VERSION 5.7 ;
  NOWIREEXTENSIONATPIN ON ;
  DIVIDERCHAR "/" ;
  BUSBITCHARS "[]" ;
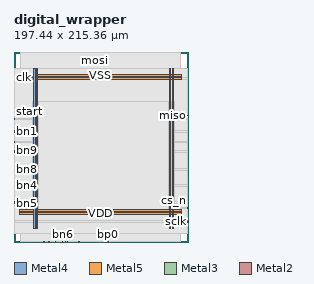
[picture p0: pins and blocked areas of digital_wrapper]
MACRO digital_wrapper
  CLASS BLOCK ;
  FOREIGN digital_wrapper ;
  ORIGIN 0.000 0.000 ;
  SIZE 197.440 BY 215.360 ;
  PIN VDD
    DIRECTION INOUT ;
    USE POWER ;
    PORT
      LAYER Metal4 ;
        RECT 22.240 15.380 23.840 196.300 ;
    END
    PORT
      LAYER Metal4 ;
        RECT 175.840 15.380 177.440 196.300 ;
    END
    PORT
      LAYER Metal5 ;
        RECT 6.720 31.530 190.400 33.130 ;
    END
    PORT
      LAYER Metal5 ;
        RECT 6.720 184.710 190.400 186.310 ;
    END
  END VDD
  PIN VSS
    DIRECTION INOUT ;
    USE GROUND ;
    PORT
      LAYER Metal4 ;
        RECT 25.540 15.380 27.140 196.300 ;
    END
    PORT
      LAYER Metal4 ;
        RECT 179.140 15.380 180.740 196.300 ;
    END
    PORT
      LAYER Metal5 ;
        RECT 6.720 34.830 190.400 36.430 ;
    END
    PORT
      LAYER Metal5 ;
        RECT 6.720 188.010 190.400 189.610 ;
    END
  END VSS
  PIN bist_en
    DIRECTION OUTPUT ;
    USE SIGNAL ;
    ANTENNADIFFAREA 0.360800 ;
    PORT
      LAYER Metal3 ;
        RECT 196.880 22.400 197.440 22.960 ;
    END
  END bist_en
  PIN bn0
    DIRECTION OUTPUT ;
    USE SIGNAL ;
    ANTENNADIFFAREA 0.897600 ;
    PORT
      LAYER Metal2 ;
        RECT 105.280 0.000 105.840 0.560 ;
    END
  END bn0
  PIN bn1
    DIRECTION OUTPUT ;
    USE SIGNAL ;
    ANTENNADIFFAREA 0.897600 ;
    PORT
      LAYER Metal3 ;
        RECT 0.000 125.440 0.560 126.000 ;
    END
  END bn1
  PIN bn2
    DIRECTION OUTPUT ;
    USE SIGNAL ;
    ANTENNADIFFAREA 0.897600 ;
    PORT
      LAYER Metal2 ;
        RECT 47.040 0.000 47.600 0.560 ;
    END
  END bn2
  PIN bn3
    DIRECTION OUTPUT ;
    USE SIGNAL ;
    ANTENNADIFFAREA 0.897600 ;
    PORT
      LAYER Metal2 ;
        RECT 60.480 0.000 61.040 0.560 ;
    END
  END bn3
  PIN bn4
    DIRECTION OUTPUT ;
    USE SIGNAL ;
    ANTENNADIFFAREA 0.897600 ;
    PORT
      LAYER Metal3 ;
        RECT 0.000 63.840 0.560 64.400 ;
    END
  END bn4
  PIN bn5
    DIRECTION OUTPUT ;
    USE SIGNAL ;
    ANTENNADIFFAREA 0.897600 ;
    PORT
      LAYER Metal3 ;
        RECT 0.000 43.680 0.560 44.240 ;
    END
  END bn5
  PIN bn6
    DIRECTION OUTPUT ;
    USE SIGNAL ;
    ANTENNADIFFAREA 0.897600 ;
    PORT
      LAYER Metal2 ;
        RECT 54.880 0.000 55.440 0.560 ;
    END
  END bn6
  PIN bn7
    DIRECTION OUTPUT ;
    USE SIGNAL ;
    ANTENNADIFFAREA 0.897600 ;
    PORT
      LAYER Metal2 ;
        RECT 33.600 0.000 34.160 0.560 ;
    END
  END bn7
  PIN bn8
    DIRECTION OUTPUT ;
    USE SIGNAL ;
    ANTENNADIFFAREA 0.897600 ;
    PORT
      LAYER Metal3 ;
        RECT 0.000 81.760 0.560 82.320 ;
    END
  END bn8
  PIN bn9
    DIRECTION OUTPUT ;
    USE SIGNAL ;
    ANTENNADIFFAREA 0.897600 ;
    PORT
      LAYER Metal3 ;
        RECT 0.000 103.040 0.560 103.600 ;
    END
  END bn9
  PIN bp0
    DIRECTION OUTPUT ;
    USE SIGNAL ;
    ANTENNADIFFAREA 0.897600 ;
    PORT
      LAYER Metal2 ;
        RECT 106.400 0.000 106.960 0.560 ;
    END
  END bp0
  PIN bp1
    DIRECTION OUTPUT ;
    USE SIGNAL ;
    ANTENNADIFFAREA 0.897600 ;
    PORT
      LAYER Metal3 ;
        RECT 0.000 124.320 0.560 124.880 ;
    END
  END bp1
  PIN bp2
    DIRECTION OUTPUT ;
    USE SIGNAL ;
    ANTENNADIFFAREA 0.897600 ;
    PORT
      LAYER Metal2 ;
        RECT 58.240 0.000 58.800 0.560 ;
    END
  END bp2
  PIN bp3
    DIRECTION OUTPUT ;
    USE SIGNAL ;
    ANTENNADIFFAREA 0.897600 ;
    PORT
      LAYER Metal2 ;
        RECT 73.920 0.000 74.480 0.560 ;
    END
  END bp3
  PIN bp4
    DIRECTION OUTPUT ;
    USE SIGNAL ;
    ANTENNADIFFAREA 0.897600 ;
    PORT
      LAYER Metal3 ;
        RECT 0.000 62.720 0.560 63.280 ;
    END
  END bp4
  PIN bp5
    DIRECTION OUTPUT ;
    USE SIGNAL ;
    ANTENNADIFFAREA 0.897600 ;
    PORT
      LAYER Metal3 ;
        RECT 0.000 44.800 0.560 45.360 ;
    END
  END bp5
  PIN bp6
    DIRECTION OUTPUT ;
    USE SIGNAL ;
    ANTENNADIFFAREA 0.897600 ;
    PORT
      LAYER Metal2 ;
        RECT 72.800 0.000 73.360 0.560 ;
    END
  END bp6
  PIN bp7
    DIRECTION OUTPUT ;
    USE SIGNAL ;
    ANTENNADIFFAREA 0.897600 ;
    PORT
      LAYER Metal2 ;
        RECT 39.200 0.000 39.760 0.560 ;
    END
  END bp7
  PIN bp8
    DIRECTION OUTPUT ;
    USE SIGNAL ;
    ANTENNADIFFAREA 0.897600 ;
    PORT
      LAYER Metal3 ;
        RECT 0.000 82.880 0.560 83.440 ;
    END
  END bp8
  PIN bp9
    DIRECTION OUTPUT ;
    USE SIGNAL ;
    ANTENNADIFFAREA 0.897600 ;
    PORT
      LAYER Metal3 ;
        RECT 0.000 101.920 0.560 102.480 ;
    END
  END bp9
  PIN clk
    DIRECTION INPUT ;
    USE SIGNAL ;
    ANTENNAGATEAREA 4.738000 ;
    PORT
      LAYER Metal3 ;
        RECT 0.000 185.920 0.560 186.480 ;
    END
  END clk
  PIN comp_in
    DIRECTION INPUT ;
    USE SIGNAL ;
    ANTENNAGATEAREA 0.396000 ;
    PORT
      LAYER Metal3 ;
        RECT 0.000 113.120 0.560 113.680 ;
    END
  END comp_in
  PIN cs_n
    DIRECTION INPUT ;
    USE SIGNAL ;
    ANTENNAGATEAREA 0.396000 ;
    PORT
      LAYER Metal3 ;
        RECT 196.880 38.080 197.440 38.640 ;
    END
  END cs_n
  PIN miso
    DIRECTION OUTPUT ;
    USE SIGNAL ;
    ANTENNADIFFAREA 0.897600 ;
    PORT
      LAYER Metal3 ;
        RECT 196.880 143.360 197.440 143.920 ;
    END
  END miso
  PIN mosi
    DIRECTION INPUT ;
    USE SIGNAL ;
    ANTENNAGATEAREA 0.396000 ;
    PORT
      LAYER Metal2 ;
        RECT 91.840 214.800 92.400 215.360 ;
    END
  END mosi
  PIN rst_n
    DIRECTION INPUT ;
    USE SIGNAL ;
    ANTENNAGATEAREA 0.396000 ;
    PORT
      LAYER Metal3 ;
        RECT 0.000 184.800 0.560 185.360 ;
    END
  END rst_n
  PIN sclk
    DIRECTION INPUT ;
    USE SIGNAL ;
    ANTENNAGATEAREA 0.396000 ;
    PORT
      LAYER Metal3 ;
        RECT 196.880 23.520 197.440 24.080 ;
    END
  END sclk
  PIN start
    DIRECTION INPUT ;
    USE SIGNAL ;
    ANTENNAGATEAREA 0.396000 ;
    PORT
      LAYER Metal3 ;
        RECT 0.000 138.880 0.560 139.440 ;
    END
  END start
  OBS
      LAYER Nwell ;
        RECT 6.290 15.250 190.830 196.430 ;
      LAYER Metal1 ;
        RECT 6.720 15.380 190.400 196.300 ;
      LAYER Metal2 ;
        RECT 7.420 214.500 91.540 214.800 ;
        RECT 92.700 214.500 188.580 214.800 ;
        RECT 7.420 0.860 188.580 214.500 ;
        RECT 7.420 0.560 33.300 0.860 ;
        RECT 34.460 0.560 38.900 0.860 ;
        RECT 40.060 0.560 46.740 0.860 ;
        RECT 47.900 0.560 54.580 0.860 ;
        RECT 55.740 0.560 57.940 0.860 ;
        RECT 59.100 0.560 60.180 0.860 ;
        RECT 61.340 0.560 72.500 0.860 ;
        RECT 74.780 0.560 104.980 0.860 ;
        RECT 107.260 0.560 188.580 0.860 ;
      LAYER Metal3 ;
        RECT 0.560 186.780 196.880 196.140 ;
        RECT 0.860 184.500 196.880 186.780 ;
        RECT 0.560 144.220 196.880 184.500 ;
        RECT 0.560 143.060 196.580 144.220 ;
        RECT 0.560 139.740 196.880 143.060 ;
        RECT 0.860 138.580 196.880 139.740 ;
        RECT 0.560 126.300 196.880 138.580 ;
        RECT 0.860 124.020 196.880 126.300 ;
        RECT 0.560 113.980 196.880 124.020 ;
        RECT 0.860 112.820 196.880 113.980 ;
        RECT 0.560 103.900 196.880 112.820 ;
        RECT 0.860 101.620 196.880 103.900 ;
        RECT 0.560 83.740 196.880 101.620 ;
        RECT 0.860 81.460 196.880 83.740 ;
        RECT 0.560 64.700 196.880 81.460 ;
        RECT 0.860 62.420 196.880 64.700 ;
        RECT 0.560 45.660 196.880 62.420 ;
        RECT 0.860 43.380 196.880 45.660 ;
        RECT 0.560 38.940 196.880 43.380 ;
        RECT 0.560 37.780 196.580 38.940 ;
        RECT 0.560 24.380 196.880 37.780 ;
        RECT 0.560 22.100 196.580 24.380 ;
        RECT 0.560 9.100 196.880 22.100 ;
      LAYER Metal4 ;
        RECT 20.860 32.570 21.940 158.950 ;
        RECT 24.140 32.570 25.240 158.950 ;
        RECT 27.440 32.570 175.540 158.950 ;
        RECT 177.740 32.570 178.840 158.950 ;
        RECT 181.040 32.570 181.860 158.950 ;
  END
END digital_wrapper
END LIBRARY

